One B-rep face of a CAD part: STEP entity #962.
In plain terms, the planar face has unit normal (1, 0, 0).
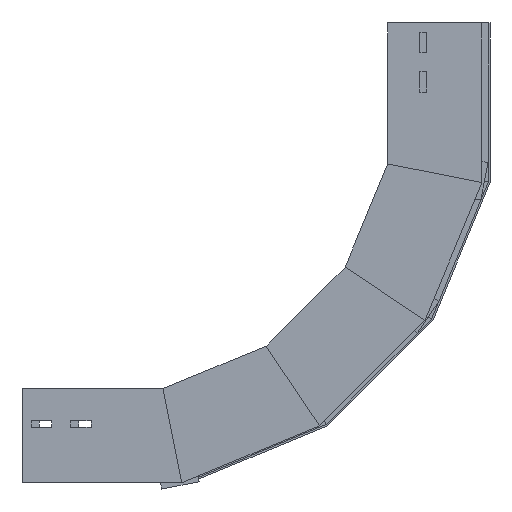
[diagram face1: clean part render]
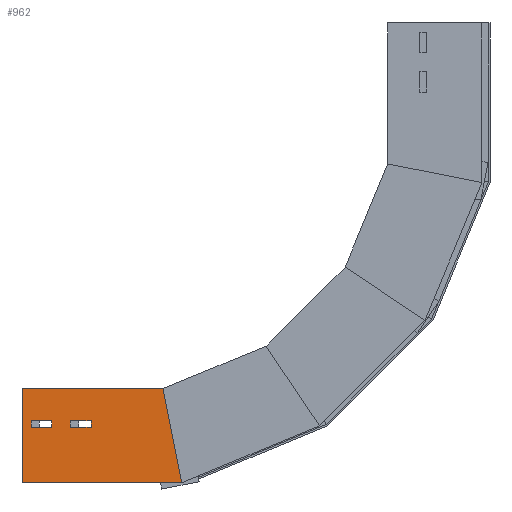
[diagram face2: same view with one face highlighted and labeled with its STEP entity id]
Its self-contained STEP definition (entity closure, numbers rounded to 3 decimals):
#12 = EDGE_CURVE ( 'NONE', #1190, #849, #1645, .T. ) ;
#37 = CARTESIAN_POINT ( 'NONE',  ( 0., 32.452, -163.145 ) ) ;
#38 = EDGE_LOOP ( 'NONE', ( #489, #1158, #1674, #1315 ) ) ;
#40 = CARTESIAN_POINT ( 'NONE',  ( 0., 59., -73.505 ) ) ;
#47 = VECTOR ( 'NONE', #92, 1000. ) ;
#53 = EDGE_CURVE ( 'NONE', #447, #72, #1776, .T. ) ;
#69 = ORIENTED_EDGE ( 'NONE', *, *, #473, .T. ) ;
#72 = VERTEX_POINT ( 'NONE', #1058 ) ;
#92 = DIRECTION ( 'NONE',  ( 0., 1., 0. ) ) ;
#113 = LINE ( 'NONE', #1564, #823 ) ;
#145 = DIRECTION ( 'NONE',  ( 0., 0., -1. ) ) ;
#153 = DIRECTION ( 'NONE',  ( 0., 0., -1. ) ) ;
#183 = DIRECTION ( 'NONE',  ( 0., -1., 0. ) ) ;
#223 = VECTOR ( 'NONE', #1808, 1000. ) ;
#255 = VECTOR ( 'NONE', #511, 1000. ) ;
#262 = CARTESIAN_POINT ( 'NONE',  ( 0., 66., -73.505 ) ) ;
#284 = VECTOR ( 'NONE', #926, 1000. ) ;
#305 = CARTESIAN_POINT ( 'NONE',  ( 0., 0., 0. ) ) ;
#338 = CARTESIAN_POINT ( 'NONE',  ( 0., 66., -73.505 ) ) ;
#342 = FACE_BOUND ( 'NONE', #1591, .T. ) ;
#350 = EDGE_LOOP ( 'NONE', ( #617, #1444, #360, #1146 ) ) ;
#358 = FACE_OUTER_BOUND ( 'NONE', #38, .T. ) ;
#360 = ORIENTED_EDGE ( 'NONE', *, *, #1235, .T. ) ;
#366 = VERTEX_POINT ( 'NONE', #453 ) ;
#367 = FACE_BOUND ( 'NONE', #350, .T. ) ;
#384 = LINE ( 'NONE', #1274, #47 ) ;
#400 = CARTESIAN_POINT ( 'NONE',  ( 0., 66., -9.835 ) ) ;
#408 = CARTESIAN_POINT ( 'NONE',  ( 0., 59., -51.505 ) ) ;
#414 = EDGE_CURVE ( 'NONE', #1801, #1692, #1820, .T. ) ;
#447 = VERTEX_POINT ( 'NONE', #1790 ) ;
#453 = CARTESIAN_POINT ( 'NONE',  ( 0., 59., -31.835 ) ) ;
#455 = LINE ( 'NONE', #1020, #1264 ) ;
#473 = EDGE_CURVE ( 'NONE', #564, #1773, #1339, .T. ) ;
#479 = CARTESIAN_POINT ( 'NONE',  ( 0., 0., -169.6 ) ) ;
#489 = ORIENTED_EDGE ( 'NONE', *, *, #1206, .F. ) ;
#503 = VECTOR ( 'NONE', #153, 1000. ) ;
#511 = DIRECTION ( 'NONE',  ( 0., 0., -1. ) ) ;
#515 = CARTESIAN_POINT ( 'NONE',  ( 0., 0., 0. ) ) ;
#564 = VERTEX_POINT ( 'NONE', #262 ) ;
#617 = ORIENTED_EDGE ( 'NONE', *, *, #1309, .T. ) ;
#656 = VECTOR ( 'NONE', #183, 1000. ) ;
#678 = EDGE_CURVE ( 'NONE', #72, #564, #455, .T. ) ;
#705 = CARTESIAN_POINT ( 'NONE',  ( 0., 0., 0. ) ) ;
#730 = VERTEX_POINT ( 'NONE', #1031 ) ;
#808 = DIRECTION ( 'NONE',  ( 0., 1., 0. ) ) ;
#823 = VECTOR ( 'NONE', #1542, 1000. ) ;
#827 = CARTESIAN_POINT ( 'NONE',  ( 0., 100., 0. ) ) ;
#835 = EDGE_CURVE ( 'NONE', #366, #730, #1624, .T. ) ;
#839 = ORIENTED_EDGE ( 'NONE', *, *, #678, .T. ) ;
#849 = VERTEX_POINT ( 'NONE', #479 ) ;
#868 = CARTESIAN_POINT ( 'NONE',  ( 0., 100., -149.709 ) ) ;
#870 = CARTESIAN_POINT ( 'NONE',  ( 0., 59., -9.835 ) ) ;
#902 = LINE ( 'NONE', #305, #503 ) ;
#926 = DIRECTION ( 'NONE',  ( 0., 1., 0. ) ) ;
#941 = DIRECTION ( 'NONE',  ( -1., 0., 0. ) ) ;
#962 = ADVANCED_FACE ( 'NONE', ( #342, #358, #367 ), #1245, .F. ) ;
#994 = ORIENTED_EDGE ( 'NONE', *, *, #53, .T. ) ;
#997 = CARTESIAN_POINT ( 'NONE',  ( 0., 66., -31.835 ) ) ;
#1020 = CARTESIAN_POINT ( 'NONE',  ( 0., 66., -51.505 ) ) ;
#1031 = CARTESIAN_POINT ( 'NONE',  ( 0., 59., -9.835 ) ) ;
#1052 = EDGE_CURVE ( 'NONE', #1703, #1626, #384, .T. ) ;
#1055 = EDGE_CURVE ( 'NONE', #1773, #447, #1570, .T. ) ;
#1058 = CARTESIAN_POINT ( 'NONE',  ( 0., 66., -51.505 ) ) ;
#1098 = VECTOR ( 'NONE', #145, 1000. ) ;
#1146 = ORIENTED_EDGE ( 'NONE', *, *, #835, .T. ) ;
#1158 = ORIENTED_EDGE ( 'NONE', *, *, #1052, .F. ) ;
#1190 = VERTEX_POINT ( 'NONE', #868 ) ;
#1206 = EDGE_CURVE ( 'NONE', #1626, #1190, #1303, .T. ) ;
#1235 = EDGE_CURVE ( 'NONE', #1692, #366, #113, .T. ) ;
#1245 = PLANE ( 'NONE',  #1350 ) ;
#1264 = VECTOR ( 'NONE', #1748, 1000. ) ;
#1274 = CARTESIAN_POINT ( 'NONE',  ( 0., 0., 0. ) ) ;
#1296 = ORIENTED_EDGE ( 'NONE', *, *, #1055, .T. ) ;
#1303 = LINE ( 'NONE', #1600, #1098 ) ;
#1309 = EDGE_CURVE ( 'NONE', #730, #1801, #1601, .T. ) ;
#1315 = ORIENTED_EDGE ( 'NONE', *, *, #12, .F. ) ;
#1319 = CARTESIAN_POINT ( 'NONE',  ( 0., 66., -9.835 ) ) ;
#1339 = LINE ( 'NONE', #338, #656 ) ;
#1350 = AXIS2_PLACEMENT_3D ( 'NONE', #515, #941, #1526 ) ;
#1444 = ORIENTED_EDGE ( 'NONE', *, *, #414, .T. ) ;
#1492 = CARTESIAN_POINT ( 'NONE',  ( 0., 66., -51.505 ) ) ;
#1526 = DIRECTION ( 'NONE',  ( 0., 0., 1. ) ) ;
#1542 = DIRECTION ( 'NONE',  ( 0., -1., 0. ) ) ;
#1564 = CARTESIAN_POINT ( 'NONE',  ( 0., 66., -31.835 ) ) ;
#1570 = LINE ( 'NONE', #408, #1632 ) ;
#1591 = EDGE_LOOP ( 'NONE', ( #994, #839, #69, #1296 ) ) ;
#1600 = CARTESIAN_POINT ( 'NONE',  ( 0., 100., 0. ) ) ;
#1601 = LINE ( 'NONE', #400, #1710 ) ;
#1624 = LINE ( 'NONE', #870, #1747 ) ;
#1626 = VERTEX_POINT ( 'NONE', #827 ) ;
#1632 = VECTOR ( 'NONE', #1881, 1000. ) ;
#1645 = LINE ( 'NONE', #37, #223 ) ;
#1662 = CARTESIAN_POINT ( 'NONE',  ( 0., 66., -9.835 ) ) ;
#1674 = ORIENTED_EDGE ( 'NONE', *, *, #1771, .T. ) ;
#1692 = VERTEX_POINT ( 'NONE', #997 ) ;
#1703 = VERTEX_POINT ( 'NONE', #705 ) ;
#1710 = VECTOR ( 'NONE', #808, 1000. ) ;
#1747 = VECTOR ( 'NONE', #1774, 1000. ) ;
#1748 = DIRECTION ( 'NONE',  ( 0., 0., -1. ) ) ;
#1771 = EDGE_CURVE ( 'NONE', #1703, #849, #902, .T. ) ;
#1773 = VERTEX_POINT ( 'NONE', #40 ) ;
#1774 = DIRECTION ( 'NONE',  ( 0., 0., 1. ) ) ;
#1776 = LINE ( 'NONE', #1492, #284 ) ;
#1790 = CARTESIAN_POINT ( 'NONE',  ( 0., 59., -51.505 ) ) ;
#1801 = VERTEX_POINT ( 'NONE', #1319 ) ;
#1808 = DIRECTION ( 'NONE',  ( 0., -0.981, -0.195 ) ) ;
#1820 = LINE ( 'NONE', #1662, #255 ) ;
#1881 = DIRECTION ( 'NONE',  ( 0., 0., 1. ) ) ;
